VERSION 5.8 ;
BUSBITCHARS "[]" ;
DIVIDERCHAR "/" ;
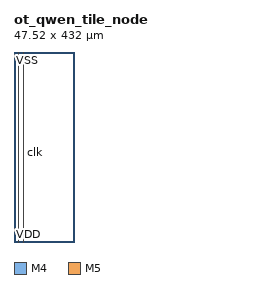
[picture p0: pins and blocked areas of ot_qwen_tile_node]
MACRO ot_qwen_tile_node
  CLASS BLOCK ;
  ORIGIN 0 0 ;
  SIZE 47.52 BY 432.0 ;
  SYMMETRY X Y ;
  PIN clk
    DIRECTION INPUT ;
    USE SIGNAL ;
    PORT
      LAYER M4 ;
        RECT 47.32 203.976 47.52 204.0 ;
    END
  END clk
  PIN VDD
    DIRECTION INOUT ;
    USE POWER ;
    PORT
      LAYER M5 ;
        RECT 10.8 0.0 10.92 432.0 ;
    END
  END VDD
  PIN VSS
    DIRECTION INOUT ;
    USE GROUND ;
    PORT
      LAYER M5 ;
        RECT 21.6 0.0 21.72 432.0 ;
    END
  END VSS
END ot_qwen_tile_node
END LIBRARY
